VERSION 5.8 ;
BUSBITCHARS "[]" ;
DIVIDERCHAR "/" ;
UNITS
  DATABASE MICRONS 1000 ;
END UNITS
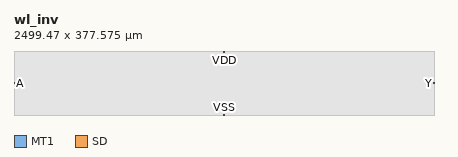
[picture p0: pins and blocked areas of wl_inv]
MACRO wl_inv
  CLASS BLOCK ;
  ORIGIN 0 0 ;
  FOREIGN wl_inv 0 0 ;
  SIZE 2499.475 BY 377.575 ;
  SYMMETRY X Y ;
  PIN A
    DIRECTION INPUT ;
    USE SIGNAL ;
    PORT
      LAYER MT1 ;
        RECT 0 186.3 5 191.3 ;
    END
  END A
  PIN Y
    DIRECTION OUTPUT ;
    USE SIGNAL ;
    PORT
      LAYER MT1 ;
        RECT 2494.475 186.3 2499.475 191.3 ;
    END
  END Y
  PIN VDD
    DIRECTION INOUT ;
    USE POWER ;
    PORT
      LAYER SD ;
        RECT 1247.25 372.575 1252.25 377.575 ;
    END
  END VDD
  PIN VSS
    DIRECTION INOUT ;
    USE GROUND ;
    PORT
      LAYER SD ;
        RECT 1247.25 0 1252.25 5 ;
    END
  END VSS
  OBS
    LAYER SD ;
      RECT 0 0 2499.475 377.575 ;
  END
END wl_inv
END LIBRARY
